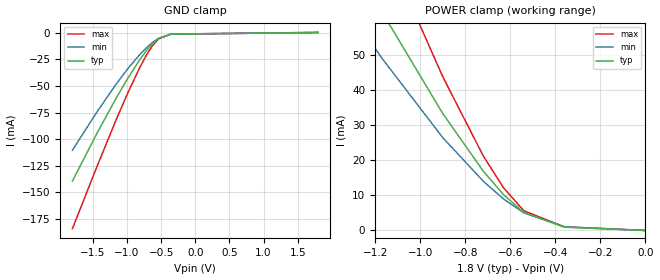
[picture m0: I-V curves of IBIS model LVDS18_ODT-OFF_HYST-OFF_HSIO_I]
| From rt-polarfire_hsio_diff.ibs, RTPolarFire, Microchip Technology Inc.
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|   Model LVDS18_ODT-OFF_HYST-OFF_HSIO_I
[Model]   LVDS18_ODT-OFF_HYST-OFF_HSIO_I
Model_type   Input
Vinl =   1.125
Vinh =   1.375
|   typ   min   max
C_comp_pullup   1.335e-12   1.335e-12   1.380e-12
C_comp_pulldown  1.335e-12   1.335e-12   1.380e-12
[Temperature Range]  25C   125C   -55C
[Voltage Range]  1.8   1.71   1.89
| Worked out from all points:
|   GND clamp passes 1 mA (typ) near -0.35 V on its own axis
|   POWER clamp passes 1 mA (typ) near -0.36 V on its own axis
[GND_clamp]
|Voltage   I(typ)   I(min)   I(max)
-1.8V     -139.5mA   -110.4mA   -184.4mA
-1.44V    -94.51mA   -74.41mA   -125.8mA
-1.17V    -62.68mA   -49.17mA   -83.45mA
-990mV    -42.83mA   -33.76mA   -56.68mA
-810mV    -24.87mA   -20.09mA   -32.14mA
-720mV    -17.03mA   -14.17mA   -21.37mA
-630mV    -10.33mA   -9.096mA   -12.29mA
-540mV    -5.237mA   -5.11mA    -5.743mA
-360mV    -1.035mA   -1.143mA   -1.143mA
1.8V      403.5uA    337.6uA    509uA
[POWER_clamp]
|Voltage   I(typ)   I(min)   I(max)
-1.8V     139.3mA    110.4mA    184.1mA
-1.44V    94.25mA    74.37mA    125.1mA
-1.17V    62.28mA    49.08mA    82.99mA
-900mV    33.34mA    26.46mA    43.82mA
-720mV    16.9mA     14.03mA    21.23mA
-630mV    10.22mA    8.983mA    12.16mA
-540mV    5.136mA    5.017mA    5.621mA
-360mV    939.1uA    1.06mA     1.025mA
0V        0A         0A         0A
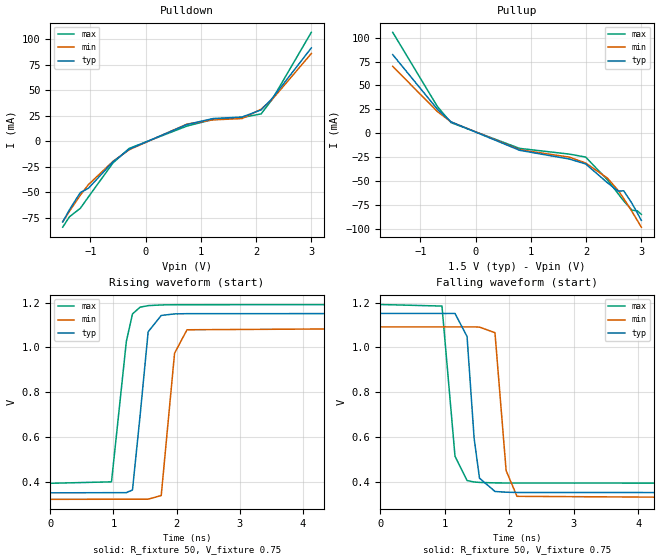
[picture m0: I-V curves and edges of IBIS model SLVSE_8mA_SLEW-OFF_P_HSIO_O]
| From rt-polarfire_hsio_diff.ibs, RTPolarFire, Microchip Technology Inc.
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|   Model SLVSE_8mA_SLEW-OFF_P_HSIO_O
[Model]   SLVSE_8mA_SLEW-OFF_P_HSIO_O
Model_type   Output
Polarity   Non-Inverting
Enable   Active-High
Vmeas =   0.2
Cref =   5p
Rref =   100
|   typ   min   max
C_comp_pullup   1.335e-12   1.335e-12   1.380e-12
C_comp_pulldown  1.335e-12   1.335e-12   1.380e-12
[Temperature Range]  25C   125C   -55C
[Voltage Range]  1.5   1.425   1.575
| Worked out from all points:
|   slope of the pulldown table from 0 to 0.225 V, typ, clamps not added: 41.3 ohm
|   slope of the pullup table from 0 to 0.225 V, typ, clamps not added: 41.3 ohm
|   rising waveform, R_fixture 50, V_fixture 0.75: 20-80 % time 141ps typ, 133ps min, 167ps max; typ from 0.35 V to 1.15 V
|   falling waveform, R_fixture 50, V_fixture 0.75: 20-80 % time 120ps typ, 115ps min, 127ps max; typ from 1.15 V to 0.35 V
[Pullup]
| Voltage   I(typ)   I(min)   I(max)
-1.5V     82.19mA    70mA       105.5mA
-689.1mV  25.02mA    22.61mA    27.84mA
-443mV    11.95mA    11.9mA     11.17mA
796.9mV   -17.71mA   -17.09mA   -15.72mA
1.697V    -26.83mA   -24.85mA   -21.69mA
1.992V    -31.94mA   -30.97mA   -24.77mA
2.386V    -51.57mA   -46.71mA   -48.55mA
2.583V    -60.43mA   -59.8mA    -63.25mA
2.681V    -60mA      -68.06mA   -70.58mA
2.829V    -72.94mA   -81.47mA   -80.19mA
2.927V    -83.06mA   -90.89mA   -80.92mA
3V        -90.94mA   -97.98mA   -84.59mA
[Pulldown]
| Voltage   I(typ)   I(min)   I(max)
-1.5V     -79.31mA   -79.09mA   -84.41mA
-1.378V   -67.37mA   -68.77mA   -74.23mA
-1.181V   -50.43mA   -53.07mA   -65.91mA
-1.034V   -46.25mA   -42.66mA   -54.69mA
-590.6mV  -20.36mA   -19.87mA   -21.46mA
-295.3mV  -7.895mA   -8.464mA   -7.13mA
750mV     16.29mA    16.72mA    14.75mA
1.219V    22.12mA    20.83mA    21.22mA
1.746V    23.62mA    22.12mA    23.15mA
2.091V    30.58mA    31.32mA    26.64mA
2.288V    41.63mA    40.66mA    40.62mA
3V        91.4mA     85.89mA    106.7mA
[Ramp]
dV/dt_r   0.48125/0.14101n  0.462711/0.13343n  0.479417/0.167473n
dV/dt_f   0.481266/0.119895n  0.462719/0.115122n  0.479412/0.126573n
R_load = 50
[Rising Waveform]
R_fixture = 50
V_fixture = 0.75
V_fixture_min = 0.7125
V_fixture_max = 0.7875
| Time   V(typ)   V(min)   V(max)
0s        350mV      320.9mV    392.6mV
969ps     350.7mV    321.3mV    399.1mV
1.204ns   350.8mV    321.4mV    1.027V
1.301ns   362.8mV    321.5mV    1.15V
1.421ns   694mV      321.5mV    1.18V
1.549ns   1.07V      321.6mV    1.187V
1.756ns   1.143V     338mV      1.19V
1.967ns   1.15V      974.3mV    1.191V
2.164ns   1.151V     1.079V     1.191V
10ns      1.152V     1.092V     1.192V
[Falling Waveform]
R_fixture = 50
V_fixture = 0.75
V_fixture_min = 0.7125
V_fixture_max = 0.7875
| Time   V(typ)   V(min)   V(max)
0s        1.152V     1.092V     1.192V
957ps     1.152V     1.092V     1.185V
1.159ns   1.152V     1.092V     513.9mV
1.346ns   1.049V     1.092V     405.2mV
1.456ns   593.4mV    1.092V     398.6mV
1.539ns   415.7mV    1.091V     396.8mV
1.779ns   356.4mV    1.066V     394.7mV
1.952ns   353mV      449.5mV    394.2mV
2.121ns   351.9mV    334.6mV    394mV
10ns      350.4mV    321.2mV    393.2mV
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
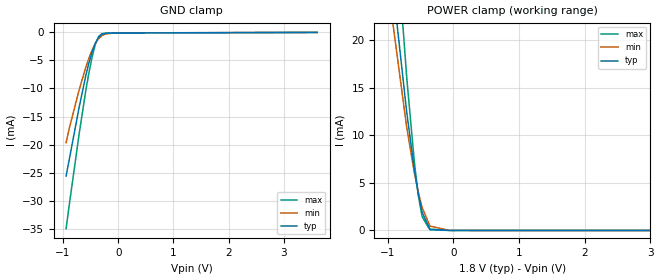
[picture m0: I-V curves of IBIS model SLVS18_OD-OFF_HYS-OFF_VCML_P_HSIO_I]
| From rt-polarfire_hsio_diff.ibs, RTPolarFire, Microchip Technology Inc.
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|   Model SLVS18_OD-OFF_HYS-OFF_VCML_P_HSIO_I
[Model]   SLVS18_OD-OFF_HYS-OFF_VCML_P_HSIO_I
Model_type   Input
Vinl =   0.275
Vinh =   0.525
|   typ   min   max
C_comp_pullup   1.335e-12   1.335e-12   1.380e-12
C_comp_pulldown  1.335e-12   1.335e-12   1.380e-12
[Temperature Range]  25C   125C   -55C
[Voltage Range]  1.8   1.71   1.89
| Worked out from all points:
|   GND clamp passes 1 mA (typ) near -0.36 V on its own axis
|   POWER clamp passes 1 mA (typ) near -0.43 V on its own axis
[GND Clamp]
| Voltage   I(typ)   I(min)   I(max)
-945mV    -25.62mA   -19.67mA   -35mA
-885.9mV  -22.59mA   -17.05mA   -30.67mA
-708.7mV  -13.38mA   -10.26mA   -18.12mA
-590.6mV  -7.834mA   -6.305mA   -10.55mA
-531.6mV  -5.448mA   -4.597mA   -7.206mA
-472.5mV  -3.431mA   -3.134mA   -4.319mA
-413.4mV  -1.876mA   -1.962mA   -2.08mA
-354.4mV  -855.7uA   -1.109mA   -722uA
-295.3mV  -345.4uA   -567.4uA   -238.2uA
-236.2mV  -166.7uA   -280.1uA   -147.2uA
-59.06mV  -101uA     -91.46uA   -123.1uA
3.6V      0A         0A         0A
[POWER Clamp]
| Voltage   I(typ)   I(min)   I(max)
-1.8V     93.14mA    78.64mA    128.6mA
-1.595V   74.66mA    64.32mA    101.3mA
-1.417V   60.09mA    52.26mA    81.74mA
-1.181V   43.08mA    36.95mA    60.78mA
-1.004V   31.04mA    26.18mA    43.79mA
-708.7mV  12.46mA    10.86mA    16.15mA
-590.6mV  6.331mA    6.031mA    7.092mA
-531.6mV  3.815mA    4.03mA     3.698mA
-472.5mV  1.865mA    2.386mA    1.443mA
-354.4mV  147uA      463.2uA    62.05uA
-59.06mV  4uA        5.688uA    5.134uA
3.6V      0A         0A         0A
